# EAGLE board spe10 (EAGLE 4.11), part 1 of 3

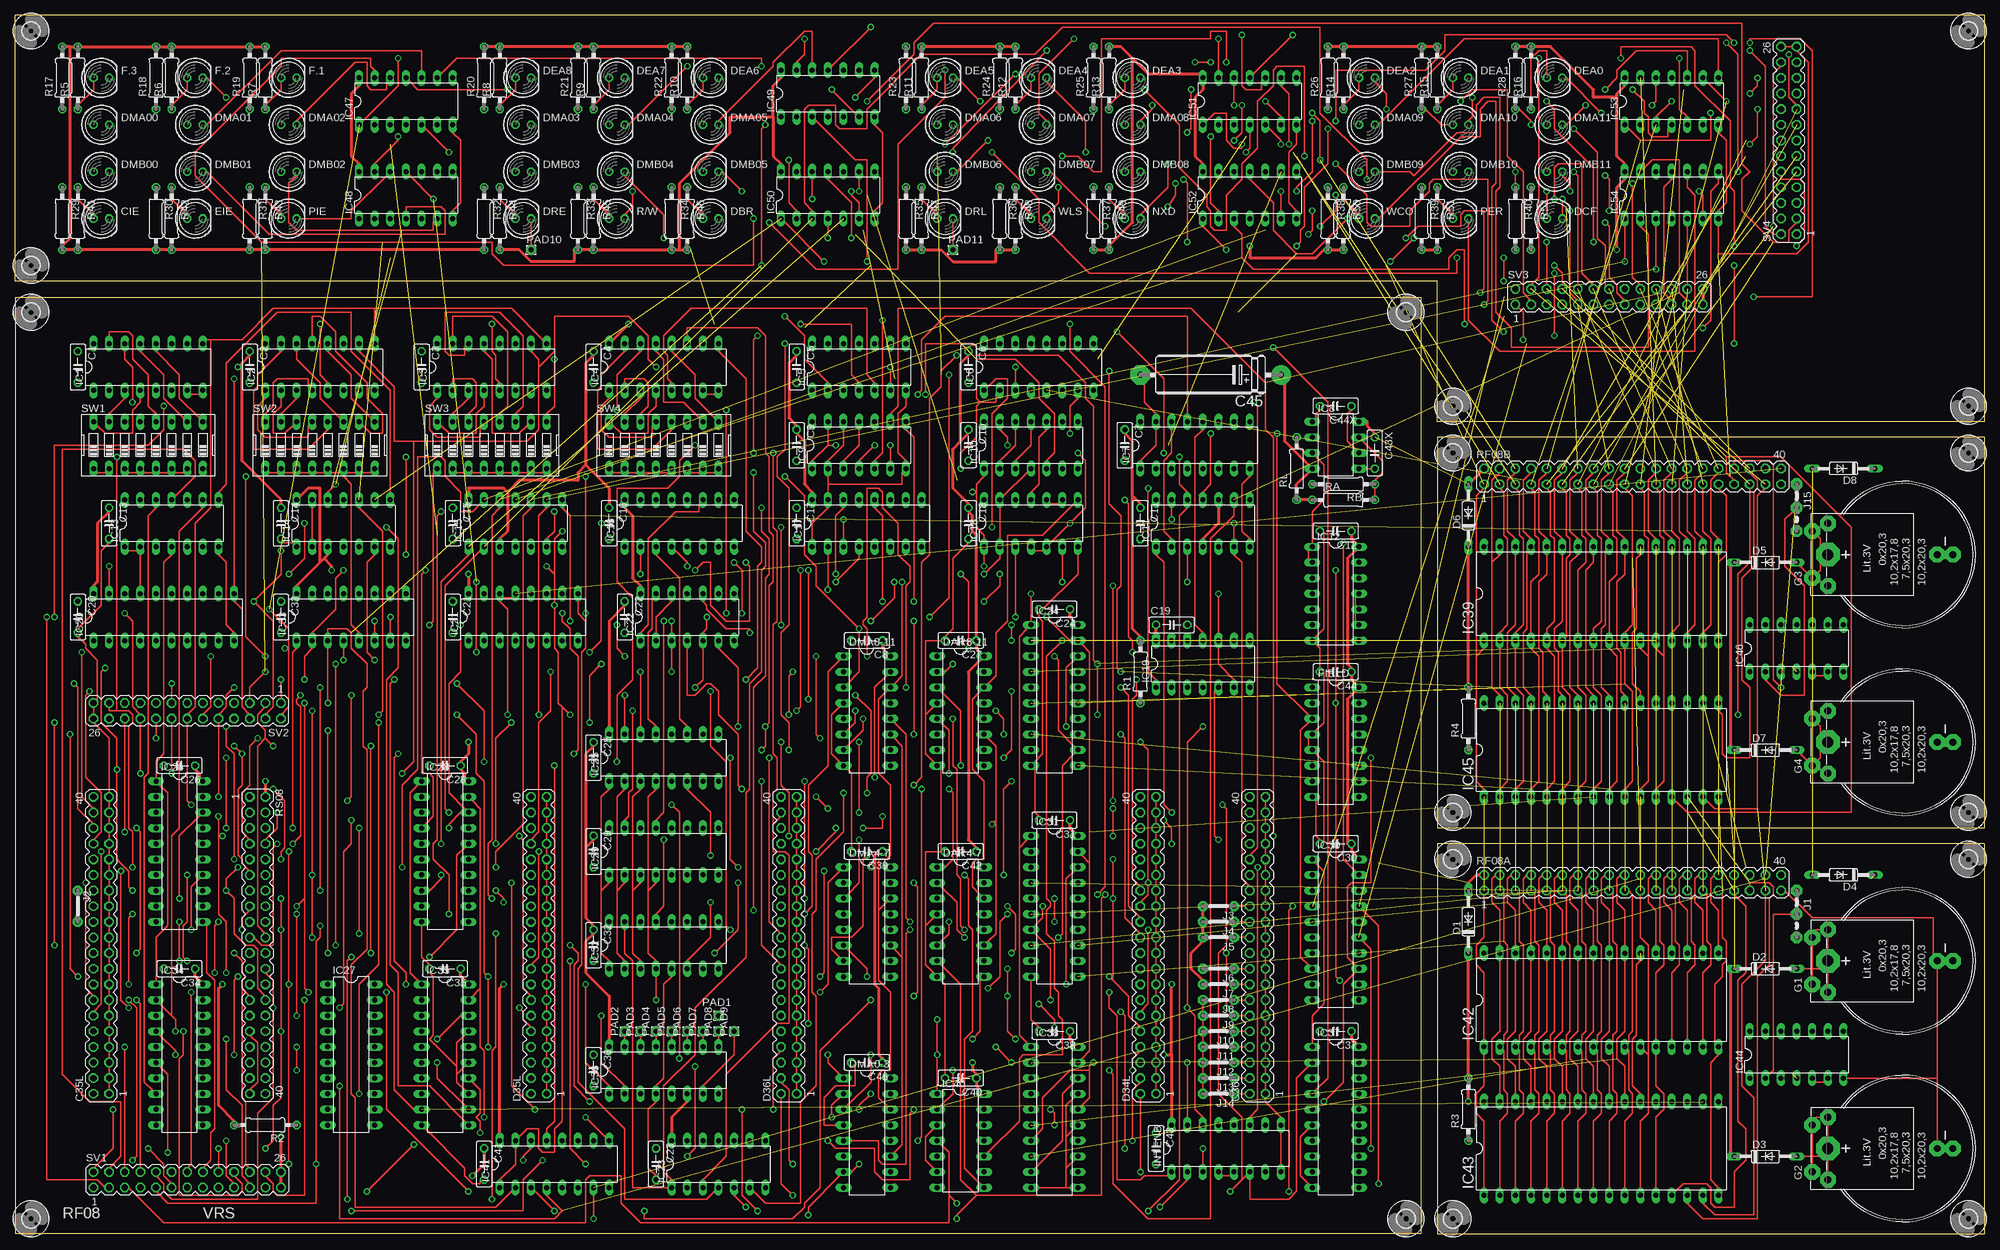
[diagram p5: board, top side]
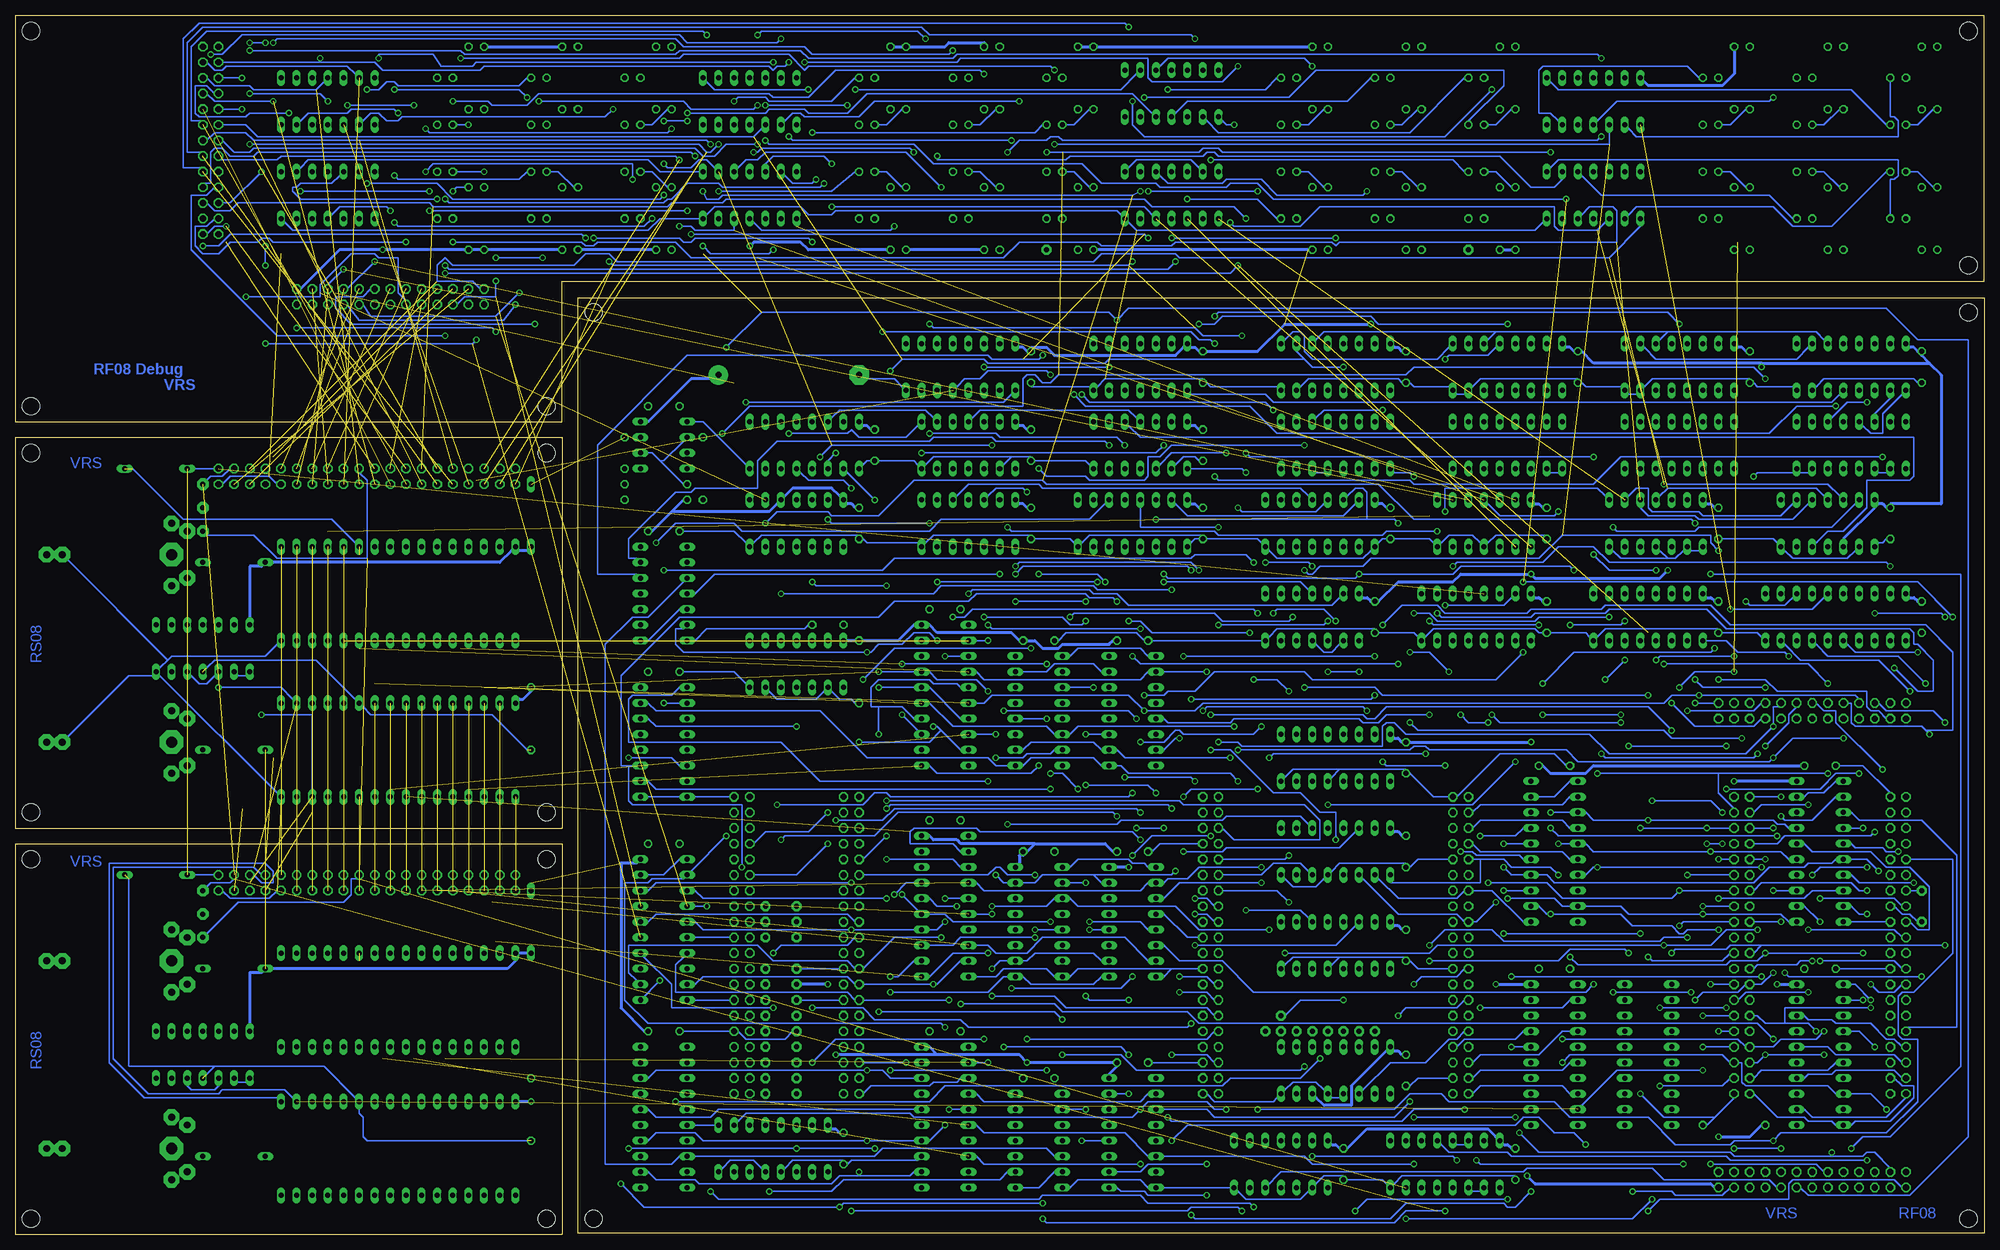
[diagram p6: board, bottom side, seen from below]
Size 320.04 x 198.12 mm. Coordinates in mm from the lower left corner, seen from the top.
Outline: 0.01,0.17 228.59,0.17 228.59,152.24 0.01,152.24 0.01,0.17
Outline: 320.04,63.5 231.14,63.5 231.14,0 320.04,0 320.04,63.5
Outline: 231.14,129.54 231.14,66.04 320.04,66.04 320.04,129.54 231.14,129.54
Outline: 320.04,132.08 231.14,132.08 231.14,154.94 0,154.94 0,198.12 320.04,198.12 320.04,132.08
Copper layers (1*16): Top 0.035mm / dielectric 1.5mm / Bottom 0.035mm
Design rules "olimex10mil": minimum track width 10mil, minimum drill 24mil, track to track 10mil, track to pad 10mil, pad to pad 10mil, via to via 10mil, smd to smd 10mil, copper to edge 40mil, drill to drill 10mil, minimum pad ring 10mil, minimum via ring 8mil, stop-mask expansion 0mil, vias tented up to drill 0mil, thermal gap 10mil
Net classes: 1 Power: width 0.508 mm

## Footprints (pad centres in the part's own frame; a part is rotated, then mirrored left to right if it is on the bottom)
C050-025X075 = drill 0.813 octagon: 1 -2.54,0; 2 2.54,0
MA20-2 = drill 1.016 octagon: 1 -24.13,-1.27; 2 -24.13,1.27; 3 -21.59,-1.27; 4 -21.59,1.27; 5 -19.05,-1.27; 6 -19.05,1.27; 7 -16.51,-1.27; 8 -16.51,1.27; 9 -13.97,-1.27; 10 -13.97,1.27; 11 -11.43,-1.27; 12 -11.43,1.27; 13 -8.89,-1.27; 14 -8.89,1.27; 15 -6.35,-1.27; 16 -6.35,1.27; 17 -3.81,-1.27; 18 -3.81,1.27; 19 -1.27,-1.27; 20 -1.27,1.27; 21 1.27,-1.27; 22 1.27,1.27; 23 3.81,-1.27; 24 3.81,1.27; 25 6.35,-1.27; 26 6.35,1.27; 27 8.89,-1.27; 28 8.89,1.27; 29 11.43,-1.27; 30 11.43,1.27; 31 13.97,-1.27; 32 13.97,1.27; 33 16.51,-1.27; 34 16.51,1.27; 35 19.05,-1.27; 36 19.05,1.27; 37 21.59,-1.27; 38 21.59,1.27; 39 24.13,-1.27; 40 24.13,1.27
E22-6 = drill 1.016 pad 3.15 round: + -11.43,0 | drill 1.016 pad 3.15 octagon: - 11.43,0
LED5MM = drill 0.813 octagon: A -1.27,0; K 1.27,0
DO35-10 = drill 0.813 long: A 5.08,0; C -5.08,0
DIL16 = drill 0.813 long: 1 -8.89,-3.81; 2 -6.35,-3.81; 3 -3.81,-3.81; 4 -1.27,-3.81; 5 1.27,-3.81; 6 3.81,-3.81; 7 6.35,-3.81; 8 8.89,-3.81; 9 8.89,3.81; 10 6.35,3.81; 11 3.81,3.81; 12 1.27,3.81; 13 -1.27,3.81; 14 -3.81,3.81; 15 -6.35,3.81; 16 -8.89,3.81
B2430UNI = drill 1.118 pad 2.54 octagon: + 3.81,14.605; +@1 -3.81,14.605; +@2 -5.08,12.065; +@3 5.08,12.065; - 0,-5.715; -@1 0,-8.255 | drill 1.803 pad 3.81 octagon: +@4 0,12.065
DIL14 = drill 0.813 long: 1 -7.62,-3.81; 2 -5.08,-3.81; 3 -2.54,-3.81; 4 0,-3.81; 5 2.54,-3.81; 6 5.08,-3.81; 7 7.62,-3.81; 8 7.62,3.81; 9 5.08,3.81; 10 2.54,3.81; 11 0,3.81; 12 -2.54,3.81; 13 -5.08,3.81; 14 -7.62,3.81
DIL08 = drill 0.813 long: 1 -3.81,-3.81; 2 -1.27,-3.81; 3 1.27,-3.81; 4 3.81,-3.81; 5 3.81,3.81; 6 1.27,3.81; 7 -1.27,3.81; 8 -3.81,3.81
DIL20 = drill 0.813 long: 1 -11.43,-3.81; 2 -8.89,-3.81; 3 -6.35,-3.81; 4 -3.81,-3.81; 5 -1.27,-3.81; 6 1.27,-3.81; 7 3.81,-3.81; 8 6.35,-3.81; 9 8.89,-3.81; 10 11.43,-3.81; 11 11.43,3.81; 12 8.89,3.81; 13 6.35,3.81; 14 3.81,3.81; 15 1.27,3.81; 16 -1.27,3.81; 17 -3.81,3.81; 18 -6.35,3.81; 19 -8.89,3.81; 20 -11.43,3.81
DIL32 = drill 0.813 long: 1 -19.05,-7.62; 2 -16.51,-7.62; 3 -13.97,-7.62; 4 -11.43,-7.62; 5 -8.89,-7.62; 6 -6.35,-7.62; 7 -3.81,-7.62; 8 -1.27,-7.62; 9 1.27,-7.62; 10 3.81,-7.62; 11 6.35,-7.62; 12 8.89,-7.62; 13 11.43,-7.62; 14 13.97,-7.62; 15 16.51,-7.62; 16 19.05,-7.62; 17 19.05,7.62; 18 16.51,7.62; 19 13.97,7.62; 20 11.43,7.62; 21 8.89,7.62; 22 6.35,7.62; 23 3.81,7.62; 24 1.27,7.62; 25 -1.27,7.62; 26 -3.81,7.62; 27 -6.35,7.62; 28 -8.89,7.62; 29 -11.43,7.62; 30 -13.97,7.62; 31 -16.51,7.62; 32 -19.05,7.62
04C = drill 0.813 pad 1.905 octagon: 1 -1.905,0; 2 1.905,0; 3 5.715,0
05 = drill 0.813 pad 1.6 octagon: 1 -2.54,0; 2 2.54,0
1,6/0,8 = drill 0.813 pad 1.6 octagon: 1 0,0
0207/10 = drill 0.813 octagon: 1 -5.08,0; 2 5.08,0
MA13-2 = drill 1.016 octagon: 1 -15.24,-1.27; 2 -15.24,1.27; 3 -12.7,-1.27; 4 -12.7,1.27; 5 -10.16,-1.27; 6 -10.16,1.27; 7 -7.62,-1.27; 8 -7.62,1.27; 9 -5.08,-1.27; 10 -5.08,1.27; 11 -2.54,-1.27; 12 -2.54,1.27; 13 0,-1.27; 14 0,1.27; 15 2.54,-1.27; 16 2.54,1.27; 17 5.08,-1.27; 18 5.08,1.27; 19 7.62,-1.27; 20 7.62,1.27; 21 10.16,-1.27; 22 10.16,1.27; 23 12.7,-1.27; 24 12.7,1.27; 25 15.24,-1.27; 26 15.24,1.27
EDG-08 = drill 0.813 long: 1 -8.89,-3.81; 2 -6.35,-3.81; 3 -3.81,-3.81; 4 -1.27,-3.81; 5 1.27,-3.81; 6 3.81,-3.81; 7 6.35,-3.81; 8 8.89,-3.81; 9 8.89,3.81; 10 6.35,3.81; 11 3.81,3.81; 12 1.27,3.81; 13 -1.27,3.81; 14 -3.81,3.81; 15 -6.35,3.81; 16 -8.89,3.81
2,8 = hole 2.8: 0,0

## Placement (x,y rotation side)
C1  0.1  [C050-025X075]  10.16,140.97 270 top
C2  0.1  [C050-025X075]  38.1,140.97 270 top
C3  0.1  [C050-025X075]  66.04,140.97 270 top
C4  0.1  [C050-025X075]  93.98,140.97 270 top
C5  0.1  [C050-025X075]  127,140.97 270 top
C6  0.1  [C050-025X075]  154.94,140.97 270 top
C7  0.1  [C050-025X075]  180.34,128.27 270 top
C8  0.1  [C050-025X075]  138.43,96.52 180 top
C9  0.1  [C050-025X075]  127,128.27 270 top
C10  0.1  [C050-025X075]  154.94,128.27 270 top
C11  0.1  [C050-025X075]  182.88,115.57 270 top
C12  0.1  [C050-025X075]  214.63,114.3 180 top
C13  0.1  [C050-025X075]  15.24,115.57 270 top
C14  0.1  [C050-025X075]  43.18,115.57 270 top
C15  0.1  [C050-025X075]  71.12,115.57 270 top
C16  0.1  [C050-025X075]  96.52,115.57 270 top
C17  0.1  [C050-025X075]  127,115.57 270 top
C18  0.1  [C050-025X075]  154.94,115.57 270 top
C19  0.1  [C050-025X075]  187.96,99.06 0 top
C20  0.1  [C050-025X075]  10.16,100.33 270 top
C21  0.1  [C050-025X075]  71.12,100.33 270 top
C22  0.1  [C050-025X075]  99.06,100.33 270 top
C23  0.1  [C050-025X075]  104.14,11.43 270 top
C24  0.1  [C050-025X075]  168.91,101.6 180 top
C25  0.1  [C050-025X075]  93.98,77.47 270 top
C26  0.1  [C050-025X075]  26.67,76.2 180 top
C27  0.1  [C050-025X075]  153.67,96.52 180 top
C28  0.1  [C050-025X075]  69.85,76.2 180 top
C29  0.1  [C050-025X075]  93.98,62.23 270 top
C30  0.1  [C050-025X075]  214.63,63.5 180 top
C31  0.1  [C050-025X075]  168.91,67.31 180 top
C32  0.1  [C050-025X075]  93.98,46.99 270 top
C33  0.1  [C050-025X075]  43.18,100.33 270 top
C34  0.1  [C050-025X075]  26.67,43.18 180 top
C35  0.1  [C050-025X075]  69.85,43.18 180 top
C35L  [MA20-2]  13.97,46.99 90 top
C36  0.1  [C050-025X075]  93.98,26.67 270 top
C36L  [MA20-2]  201.93,46.99 90 top
C37  0.1  [C050-025X075]  214.63,33.02 180 top
C38  0.1  [C050-025X075]  168.91,33.02 180 top
C39  0.1  [C050-025X075]  138.43,62.23 180 top
C40  0.1  [C050-025X075]  153.67,25.4 180 top
C41  0.1  [C050-025X075]  76.2,11.43 270 top
C42  0.1  [C050-025X075]  153.67,62.23 180 top
C43  0.1  [C050-025X075]  185.42,13.97 270 top
C43X  .1uf  [C050-025X075]  220.98,127 270 top
C44  0.1  [C050-025X075]  214.63,91.44 180 top
C44X  .1uf  [C050-025X075]  214.63,134.62 180 top
C45  100uf  [E22-6]  194.31,139.7 180 top
C46  0.1  [C050-025X075]  138.43,27.94 180 top
CIE  [LED5MM]  13.97,165.1 0 top
D1  1N4148  [DO35-10]  236.22,50.8 90 top
D2  1N4148  [DO35-10]  284.48,43.18 0 top
D3  1N4148  [DO35-10]  284.48,12.7 0 top
D4  1N4148  [DO35-10]  297.18,58.42 180 top
D5  1N4148  [DO35-10]  284.48,109.22 0 top
D6  1N4148  [DO35-10]  236.22,116.84 90 top
D7  1N4148  [DO35-10]  284.48,78.74 0 top
D8  1N4148  [DO35-10]  297.18,124.46 180 top
D34L  [MA20-2]  184.15,46.99 90 top
D35L  [MA20-2]  85.09,46.99 90 top
D36L  [MA20-2]  125.73,46.99 90 top
DAR4-7  74LS193N  [DIL16]  153.67,50.8 270 top
DAR8-11  74LS193N  [DIL16]  153.67,85.09 270 top
DBR  [LED5MM]  113.03,165.1 0 top
DCF  [LED5MM]  250.19,165.1 0 top
DEA0  [LED5MM]  250.19,187.96 0 top
DEA1  [LED5MM]  234.95,187.96 0 top
DEA2  [LED5MM]  219.71,187.96 0 top
DEA3  [LED5MM]  181.61,187.96 0 top
DEA4  [LED5MM]  166.37,187.96 0 top
DEA5  [LED5MM]  151.13,187.96 0 top
DEA6  [LED5MM]  113.03,187.96 0 top
DEA7  [LED5MM]  97.79,187.96 0 top
DEA8  [LED5MM]  82.55,187.96 0 top
DMA00  [LED5MM]  13.97,180.34 0 top
DMA0-3  74LS193N  [DIL16]  138.43,16.51 270 top
DMA01  [LED5MM]  29.21,180.34 0 top
DMA02  [LED5MM]  44.45,180.34 0 top
DMA03  [LED5MM]  82.55,180.34 0 top
DMA04  [LED5MM]  97.79,180.34 0 top
DMA4-7  74LS193N  [DIL16]  138.43,50.8 270 top
DMA05  [LED5MM]  113.03,180.34 0 top
DMA06  [LED5MM]  151.13,180.34 0 top
DMA07  [LED5MM]  166.37,180.34 0 top
DMA08  [LED5MM]  181.61,180.34 0 top
DMA8-11  74LS193N  [DIL16]  138.43,85.09 270 top
DMA09  [LED5MM]  219.71,180.34 0 top
DMA10  [LED5MM]  234.95,180.34 0 top
DMA11  [LED5MM]  250.19,180.34 0 top
DMB00  [LED5MM]  13.97,172.72 0 top
DMB01  [LED5MM]  29.21,172.72 0 top
DMB02  [LED5MM]  44.45,172.72 0 top
DMB03  [LED5MM]  82.55,172.72 0 top
DMB04  [LED5MM]  97.79,172.72 0 top
DMB05  [LED5MM]  113.03,172.72 0 top
DMB06  [LED5MM]  151.13,172.72 0 top
DMB07  [LED5MM]  166.37,172.72 0 top
DMB08  [LED5MM]  181.61,172.72 0 top
DMB09  [LED5MM]  219.71,172.72 0 top
DMB10  [LED5MM]  234.95,172.72 0 top
DMB11  [LED5MM]  250.19,172.72 0 top
DRE  [LED5MM]  82.55,165.1 0 top
DRL  [LED5MM]  151.13,165.1 0 top
EIE  [LED5MM]  29.21,165.1 0 top
F.1  [LED5MM]  44.45,187.96 0 top
F.2  [LED5MM]  29.21,187.96 0 top
F.3  [LED5MM]  13.97,187.96 0 top
FIELD  74LS193N  [DIL16]  214.63,80.01 270 top
G1  B2430UNI  [B2430UNI]  306.7,44.45 90 top
G2  B2430UNI  [B2430UNI]  306.7,13.97 90 top
G3  B2430UNI  [B2430UNI]  306.7,110.49 90 top
G4  B2430UNI  [B2430UNI]  306.7,80.01 90 top
IC1  74LS151N  [DIL16]  21.59,140.97 0 top
IC2  74LS151N  [DIL16]  49.53,140.97 0 top
IC3  74LS151N  [DIL16]  77.47,140.97 0 top
IC4  74LS151N  [DIL16]  105.41,140.97 0 top
IC5  74LS20N  [DIL14]  137.16,140.97 0 top
IC6  74S139N  [DIL16]  166.37,140.97 0 top
IC7  74LS139N  [DIL16]  191.77,128.27 0 top
IC8  LM555N  [DIL08]  214.63,128.27 270 top
IC9  74S74N  [DIL14]  137.16,128.27 0 top
IC10  74S74N  [DIL14]  165.1,128.27 0 top
IC11  74S74N  [DIL14]  193.04,115.57 0 top
IC12  74LS00N  [DIL14]  214.63,104.14 270 top
IC13  74180N  [DIL14]  25.4,115.57 0 top
IC14  74180N  [DIL14]  53.34,115.57 0 top
IC15  74180N  [DIL14]  81.28,115.57 0 top
IC16  74S139N  [DIL16]  107.95,115.57 0 top
IC17  74S139N  [DIL16]  138.43,115.57 0 top
IC18  74LS00N  [DIL14]  165.1,115.57 0 top
IC19  7407N  [DIL14]  193.04,92.71 0 top
IC20  74S240N  [DIL20]  24.13,100.33 0 top
IC21  74LS139N  [DIL16]  82.55,100.33 0 top
IC22  7407N  [DIL14]  109.22,100.33 0 top
IC23  74S74N  [DIL14]  114.3,11.43 0 top
IC24  74S240N  [DIL20]  168.91,87.63 270 top
IC25  74S138N  [DIL16]  105.41,77.47 0 top
IC26  74S240N  [DIL20]  26.67,62.23 270 top
IC27  SPARE  [DIL20]  54.61,29.21 270 top
IC28  74LS244N  [DIL20]  69.85,62.23 270 top
IC29  74S138N  [DIL16]  105.41,62.23 0 top
IC30  74S240N  [DIL20]  214.63,49.53 270 top
IC31  74S240N  [DIL20]  168.91,53.34 270 top
IC32  74S138N  [DIL16]  105.41,46.99 0 top
IC33  74LS139N  [DIL16]  54.61,100.33 0 top
IC34  74S240N  [DIL20]  26.67,29.21 270 top
IC35  74LS244N  [DIL20]  69.85,29.21 270 top
IC36  74S138N  [DIL16]  105.41,26.67 0 top
IC37  74S240N  [DIL20]  214.63,19.05 270 top
IC38  74S240N  [DIL20]  168.91,19.05 270 top
IC39  628512  [DIL32]  257.81,104.14 0 top
IC40  74S03N  [DIL14]  153.67,15.24 270 top
IC41  74LS139N  [DIL16]  87.63,11.43 0 top
IC42  628512  [DIL32]  257.81,38.1 0 top
IC43  628512  [DIL32]  257.81,13.97 0 top
IC44  4011N  [DIL14]  289.56,29.21 0 top
IC45  628512  [DIL32]  257.81,78.74 0 top
IC46  4011N  [DIL14]  289.56,95.25 0 top
IC47  7404N  [DIL14]  63.5,184.15 0 top
IC48  7404N  [DIL14]  63.5,168.91 0 top
IC49  7404N  [DIL14]  132.08,185.42 0 top
IC50  7404N  [DIL14]  132.08,168.91 0 top
IC51  7404N  [DIL14]  200.66,184.15 0 top
IC52  7404N  [DIL14]  200.66,168.91 0 top
IC53  7404N  [DIL14]  269.24,184.15 0 top
IC54  7404N  [DIL14]  269.24,168.91 0 top
INTENB  74LS193N  [DIL16]  196.85,13.97 0 top
J1  [04C]  289.56,53.98 270 top
J2  J5MM  [05]  10.16,53.34 270 top
J3  J5MM  [05]  195.58,53.34 180 top
J4  J5MM  [05]  195.58,50.8 180 top
J5  J5MM  [05]  195.58,48.26 180 top
J6  J5MM  [05]  195.58,43.18 180 top
J7  J5MM  [05]  195.58,40.64 180 top
J8  J5MM  [05]  195.58,38.1 180 top
J9  J5MM  [05]  195.58,35.56 180 top
J10  J5MM  [05]  195.58,33.02 180 top
J11  J5MM  [05]  195.58,30.48 180 top
J12  J5MM  [05]  195.58,27.94 180 top
J13  J5MM  [05]  195.58,25.4 180 top
J14  J5MM  [05]  195.58,22.86 180 top
J15  [04C]  289.56,120.02 270 top
NXD  [LED5MM]  181.61,165.1 0 top
PAD1  [1,6/0,8]  114.3,35.56 90 top
PAD2  [1,6/0,8]  99.06,33.02 90 top
PAD3  [1,6/0,8]  101.6,33.02 90 top
PAD4  [1,6/0,8]  104.14,33.02 90 top
PAD5  [1,6/0,8]  106.68,33.02 90 top
PAD6  [1,6/0,8]  109.22,33.02 90 top
PAD7  [1,6/0,8]  111.76,33.02 90 top
PAD8  [1,6/0,8]  114.3,33.02 90 top
PAD9  [1,6/0,8]  116.84,33.02 90 top
PAD10  [1,6/0,8]  83.82,160.02 0 top
PAD11  [1,6/0,8]  152.4,160.02 0 top
PER  [LED5MM]  234.95,165.1 0 top
PIE  [LED5MM]  44.45,165.1 0 top
R1  5.1K  [0207/10]  182.88,91.44 90 top
R2  5.1K  [0207/10]  40.64,17.78 180 top
R3  10 Megohm  [0207/10]  236.22,20.32 90 top
R4  10 Megohm  [0207/10]  236.22,83.82 90 top
R5  330  [0207/10]  10.16,187.96 90 top
R6  330  [0207/10]  25.4,187.96 90 top
R7  330  [0207/10]  40.64,187.96 90 top
R8  330  [0207/10]  78.74,187.96 90 top
R9  330  [0207/10]  93.98,187.96 90 top
R10  330  [0207/10]  109.22,187.96 90 top
R11  330  [0207/10]  147.32,187.96 90 top
R12  330  [0207/10]  162.56,187.96 90 top
R13  330  [0207/10]  177.8,187.96 90 top
R14  330  [0207/10]  215.9,187.96 90 top
R15  330  [0207/10]  231.14,187.96 90 top
R16  330  [0207/10]  246.38,187.96 90 top
R17  330  [0207/10]  7.62,187.96 90 top
R18  330  [0207/10]  22.86,187.96 90 top
R19  330  [0207/10]  38.1,187.96 90 top
R20  330  [0207/10]  76.2,187.96 90 top
R21  330  [0207/10]  91.44,187.96 90 top
R22  330  [0207/10]  106.68,187.96 90 top
R23  330  [0207/10]  144.78,187.96 90 top
R24  330  [0207/10]  160.02,187.96 90 top
R25  330  [0207/10]  175.26,187.96 90 top
R26  330  [0207/10]  213.36,187.96 90 top
R27  330  [0207/10]  228.6,187.96 90 top
R28  330  [0207/10]  243.84,187.96 90 top
R29  330  [0207/10]  7.62,165.1 270 top
R30  330  [0207/10]  22.86,165.1 270 top
R31  330  [0207/10]  38.1,165.1 270 top
R32  330  [0207/10]  76.2,165.1 270 top
R33  330  [0207/10]  91.44,165.1 270 top
R34  330  [0207/10]  106.68,165.1 270 top
R35  330  [0207/10]  144.78,165.1 270 top
R36  330  [0207/10]  160.02,165.1 270 top
R37  330  [0207/10]  175.26,165.1 270 top
R38  330  [0207/10]  213.36,165.1 270 top
R39  330  [0207/10]  228.6,165.1 270 top
R40  330  [0207/10]  243.84,165.1 270 top
R41  330  [0207/10]  10.16,165.1 270 top
R42  330  [0207/10]  25.4,165.1 270 top
R43  330  [0207/10]  40.64,165.1 270 top
R44  330  [0207/10]  78.74,165.1 270 top
R45  330  [0207/10]  93.98,165.1 270 top
R46  330  [0207/10]  109.22,165.1 270 top
R47  330  [0207/10]  147.32,165.1 270 top
R48  330  [0207/10]  162.56,165.1 270 top
R49  330  [0207/10]  177.8,165.1 270 top
R50  330  [0207/10]  215.9,165.1 270 top
R51  330  [0207/10]  231.14,165.1 270 top
R52  330  [0207/10]  246.38,165.1 270 top
R/W  [LED5MM]  97.79,165.1 0 top
RA  470K  [0207/10]  215.9,119.38 0 top
RB  1.5K  [0207/10]  215.9,121.92 180 top
RF08A  [MA20-2]  262.89,57.15 0 top
RF08B  [MA20-2]  262.89,123.19 0 top
RL  1K  [0207/10]  208.28,124.46 90 top
RS08  [MA20-2]  39.37,46.99 270 top
SV1  [MA13-2]  27.94,8.89 0 top
SV2  [MA13-2]  27.94,85.09 180 top
SV3  [MA13-2]  259.08,152.4 0 top
SV4  [MA13-2]  288.29,177.8 90 top
SW1  [EDG-08]  21.59,128.27 0 top
SW2  [EDG-08]  49.53,128.27 0 top
SW3  [EDG-08]  77.47,128.27 0 top
SW4  [EDG-08]  105.41,128.27 0 top
U$1  [2,8]  2.54,149.86 0 top
U$2  [2,8]  226.06,149.86 0 top
U$3  [2,8]  2.54,2.54 0 top
U$4  [2,8]  226.06,2.54 0 top
U$5  [2,8]  233.68,2.54 0 top
U$6  [2,8]  233.68,60.96 0 top
U$7  [2,8]  317.5,60.96 0 top
U$8  [2,8]  317.5,2.54 0 top
U$9  [2,8]  317.5,68.58 0 top
U$10  [2,8]  233.68,68.58 0 top
U$11  [2,8]  233.68,127 0 top
U$12  [2,8]  317.5,127 0 top
U$13  [2,8]  2.54,157.48 0 top
U$14  [2,8]  2.54,195.58 0 top
U$15  [2,8]  233.68,134.62 0 top
U$16  [2,8]  317.5,134.62 0 top
U$17  [2,8]  317.5,195.58 0 top
WCO  [LED5MM]  219.71,165.1 0 top
WLS  [LED5MM]  166.37,165.1 0 top

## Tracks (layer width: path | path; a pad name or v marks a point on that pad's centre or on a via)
3CYC\
  Bottom 0.254: C35L.28 12.06,55.88 10.79,55.88 J2.1
601\  (via drill 0.61)
  Top 0.254: IC32.15 99.06,49.53 99.06,45.72 100.33,44.45 100.33,7.62 106.05,7.62 IC23.1 106.68,8.89 105.41,10.16 105.41,24.13 110.49,29.21 110.49,36.83 118.75,45.09 118.75,71.75 119.38,72.39 119.38,89.53 121.28,91.44 121.28,107.95 121.92,108.58 121.92,112.39 120.02,114.3 v120.02,123.83 | 132.08,128.27 129.54,125.73 IC9.1 | 132.08,128.27 132.08,130.81 IC9.13 | IC18.4 165.74,111.12 167,111.12 IC18.5 168.28,112.39 v171.45,115.57 173.99,118.11 173.99,125.73 v172.72,127 | v187.96,116.2 187.96,118.11 IC11.13 | 132.08,128.27 v133.35,128.27
  Bottom 0.254: v187.96,116.2 187.32,115.57 v171.45,115.57 | v133.35,128.27 134.62,127 v172.72,127 | v120.02,123.83 120.65,124.46 128.91,124.46 IC9.1
602\  (via drill 0.61)
  Top 0.254: v100.33,85.09 100.33,72.39 99.69,71.75 99.69,67.94 99.06,67.31 IC29.15 | v127,85.09 127.64,85.72 v127.64,107.95 | v157.48,108.58 157.48,110.49 IC18.1 157.48,113.03 157.48,113.67 156.21,114.94 156.21,120.65 | 156.21,120.65 156.21,121.92 157.48,123.19 IC10.1 | 156.21,120.65 v155.57,120.65
  Bottom 0.254: v100.33,85.09 100.97,85.72 126.36,85.72 v127,85.09 | v127.64,107.95 128.91,109.22 156.84,109.22 v157.48,108.58 | v155.57,120.65 156.21,121.28 160.66,121.28 161.93,120.02 IC18.12
604\  (via drill 0.61)
  Top 0.254: v99.06,87.63 99.06,82.55 IC25.15 | v128.91,107.95 v128.91,87 | v157.48,107.31 160.02,109.86 160.02,110.49 IC18.2 160.02,113.03 160.02,118.11 IC18.13 160.66,120.02 164.47,123.83 IC10.4
  Bottom 0.254: v99.06,87.63 99.69,87 v128.91,87 | v128.91,107.95 129.54,108.58 156.21,108.58 v157.48,107.31
611\  (via drill 0.61)
  Top 0.254: v128.27,46.99 128.91,46.35 v128.91,34.29 | INTENB.14 193.04,19.05 191.77,20.32 191.77,35.56 v190.5,36.83 190.5,80.01 v193.04,82.55
  Bottom 0.254: v128.27,46.99 105.41,46.99 102.23,50.16 IC32.14 | v128.91,34.29 129.54,33.66 165.1,33.66 166.37,34.92 180.34,34.92 182.25,36.83 v190.5,36.83 | v193.04,82.55 215.9,82.55 217.17,83.82 FIELD.14
612\  (via drill 0.61)
  Top 0.254: v130.18,62.23 133.35,65.41 v133.35,66.04 | v137.79,66.04 140.97,66.04 v140.97,67.94 | v195.58,64.14 194.94,64.77 194.94,88.27 IC19.5
  Bottom 0.254: v130.18,62.23 123.83,62.23 123.19,62.87 104.78,62.87 102.23,65.41 IC29.14 | v137.79,66.04 v133.35,66.04 | v140.97,67.94 141.6,68.58 176.53,68.58 180.34,64.77 194.94,64.77 v195.58,64.14
614\  (via drill 0.61)
  Top 0.254: v101.6,91.44 101.6,82.55 IC25.14 | v106.68,91.44 106.68,95.25 IC22.3 106.68,97.79 v106.68,99.69 | v124.46,114.94 v124.46,99.06
  Bottom 0.254: v106.68,91.44 v101.6,91.44 | v124.46,114.94 137.16,114.94 137.16,118.11 IC17.13 | v124.46,99.06 107.31,99.06 v106.68,99.69
621\  (via drill 0.61)
  Top 0.254: v105.41,64.14 105.41,53.34 104.14,52.07 IC32.13 | v125.73,78.74 125.73,83.19 124.46,84.45 124.46,97.79 125.73,99.06 125.73,121.28 123.83,123.19 123.83,126.36 125.09,127.64 v125.09,144.78 | v179.07,146.69 186.69,139.06 v186.69,127
  Bottom 0.254: v105.41,64.14 105.41,68.58 107.95,68.58 111.12,71.75 115.57,71.75 122.56,78.74 v125.73,78.74 | v125.09,144.78 125.73,145.41 127.64,145.41 128.91,146.69 v179.07,146.69 | v186.69,127 187.96,125.73 IC7.3
622\  (via drill 0.61)
  Top 0.254: v105.41,99.69 105.41,68.58 104.14,67.31 IC29.13 | v115.57,133.99 v115.57,100.97 | v146.69,136.53 147.32,137.16 147.32,145.41 151.13,149.22 190.5,149.22 190.5,133.35 IC7.13
  Bottom 0.254: v105.41,99.69 107.31,101.6 114.94,101.6 v115.57,100.97 | v115.57,133.99 116.84,135.25 145.41,135.25 v146.69,136.53
624\  (via drill 0.61)
  Top 0.254: IC25.13 104.14,82.55 102.87,83.82 102.87,97.79 103.5,98.42 103.5,103.5 IC22.13 | 163.19,62.87 163.19,32.38 164.47,31.11 IC38.1 | 163.19,62.87 164.47,64.14 IC31.1 | 163.19,62.87 163.19,97.16 164.47,98.42 IC24.1 165.1,99.69 v165.1,104.14
  Bottom 0.254: v165.1,104.14 164.47,104.78 145.41,104.78 144.78,104.14 140.97,104.14 139.06,102.23 106.05,102.23 104.78,103.5 IC22.13
641\  (via drill 0.61)
  Top 0.254: v120.02,52.7 120.02,88.9 121.92,90.81 121.92,106.68 122.56,107.31 122.56,113.03 121.28,114.3 v121.28,118.11
  Bottom 0.254: v120.02,52.7 111.12,52.7 109.86,51.44 IC32.11 | v121.28,118.11 120.65,117.47 108.58,117.47 107.31,118.75 IC16.13
642\  (via drill 0.61)
  Top 0.254: v158.75,66.67 159.38,67.31 | 159.38,67.31 159.38,79.38 158.12,80.64 DAR8-11.11 | 159.38,67.31 159.38,48.9 158.12,47.62 DAR4-7.11
  Bottom 0.254: v158.75,66.67 140.97,66.67 140.34,67.31 123.83,67.31 123.19,67.94 111.12,67.94 109.86,66.67 IC29.11
644\
  Top 0.254: IC25.11 109.22,82.55 107.95,83.82 107.95,106.68 104.14,110.49 IC16.3
645\  (via drill 0.61)
  Top 0.254: 174.62,60.33 174.62,29.84 173.35,28.57 IC38.19 | 174.62,60.33 173.35,61.59 IC31.19 | 174.62,60.33 174.62,94.61 173.35,95.89 IC24.19 171.45,96.52 v167.64,100.33 | v109.22,108.58 109.22,109.22 107.31,111.12 IC16.4 | v116.84,109.22 118.11,107.95 v118.11,100.97
  Bottom 0.254: v109.22,108.58 109.86,109.22 v116.84,109.22 | v118.11,100.97 118.75,101.6 164.47,101.6 165.74,100.33 v167.64,100.33
ACB00\  (via drill 0.61)
  Top 0.254: v182.88,10.16 182.88,22.23 D34L.2
  Bottom 0.254: IC38.3 166.37,25.4 167,24.77 170.81,24.77 171.45,24.13 180.97,24.13 182.25,22.86 D34L.2 | 182.88,9.53 186.06,9.53 187.32,8.26 208.91,8.26 209.55,8.89 215.9,8.89 217.17,10.16 IC37.12 | 182.88,9.53 174.62,9.53 173.99,10.16 IC38.12 | 182.88,9.53 v182.88,10.16
ACB01\  (via drill 0.61)
  Top 0.254: v168.28,20.32 168.91,19.68 v168.91,17.78 | v181.61,15.24 181.61,23.5 182.88,24.77 D34L.4
  Bottom 0.254: IC37.14 217.17,15.24 215.9,16.51 209.55,16.51 208.28,15.24 v181.61,15.24 173.99,15.24 IC38.14 171.45,15.24 v168.91,17.78 | v168.28,20.32 166.37,20.32 IC38.5
ACB02\  (via drill 0.61)
  Top 0.254: 174.62,26.67 171.45,26.67 167,22.23 167,17.14 165.74,15.88 IC38.7 | 174.62,26.67 174.62,22.23 173.35,20.95 IC38.16 | v175.26,27.94 174.62,27.3 174.62,26.67
  Bottom 0.254: IC37.16 217.17,20.32 215.9,19.05 207.01,19.05 205.74,20.32 173.99,20.32 IC38.16 | v175.26,27.94 182.25,27.94 D34L.6
ACB03\  (via drill 0.61)
  Top 0.254: IC38.9 165.74,10.79 170.18,15.24 170.18,22.86 172.09,24.77 IC38.18 | v181.61,26.67 181.61,28.57 182.88,29.84 D34L.8
  Bottom 0.254: IC37.18 217.17,25.4 215.9,26.67 v181.61,26.67 179.07,26.67 177.8,25.4 173.99,25.4 IC38.18
ACB04\  (via drill 0.61)
  Top 0.254: 178.44,41.27 180.97,38.73 180.97,35.56 182.88,33.66 D34L.10 | 178.44,41.27 v177.8,41.91 | 178.44,41.27 v178.44,54.61 v178.44,60.96
  Bottom 0.254: v177.8,41.91 176.53,41.91 173.99,44.45 IC31.12 | v178.44,60.96 167.64,60.96 166.37,59.69 IC31.3 | v178.44,54.61 208.28,54.61 209.55,55.88 IC30.3
ACB05\  (via drill 0.61)
  Top 0.254: v168.91,50.8 v168.91,54.61 | v184.15,49.53 184.15,37.47 182.88,36.2 D34L.12
  Bottom 0.254: IC30.5 209.55,50.8 208.28,49.53 v184.15,49.53 173.99,49.53 IC31.14 171.45,49.53 170.18,49.53 v168.91,50.8 | v168.91,54.61 166.37,54.61 IC31.5
ACB06\  (via drill 0.61)
  Top 0.254: v167,53.34 167,51.44 165.74,50.16 IC31.7 165.74,48.9 168.28,46.35 v168.28,38.1
  Bottom 0.254: v167,53.34 170.18,53.34 171.45,54.61 IC31.16 | IC30.7 211.46,45.09 212.72,43.81 212.72,39.37 184.78,39.37 183.51,38.1 D34L.14 182.25,38.1 v168.28,38.1
ACB07\  (via drill 0.61)
  Top 0.254: v170.81,40.64 170.81,57.78 172.09,59.05 IC31.18
  Bottom 0.254: IC30.9 209.55,40.64 208.28,41.91 184.78,41.91 183.51,40.64 D34L.16 182.25,40.64 v170.81,40.64 170.18,40.64 166.37,44.45 IC31.9
ACB08\  (via drill 0.61)
  Top 0.254: v168.91,93.98 169.54,93.34 169.54,81.92 172.09,79.38 IC24.12 172.09,78.11 170.18,76.2 170.18,48.9 v169.54,48.26
  Bottom 0.254: v168.91,93.98 166.37,93.98 IC24.3 | IC30.12 219.07,41.27 220.34,42.55 220.34,46.99 199.39,46.99 196.85,44.45 184.78,44.45 183.51,43.18 D34L.18 182.25,43.18 177.16,48.26 v169.54,48.26
ACB09\  (via drill 0.61)
  Top 0.254: v196.85,45.72 v196.85,36.83 | v179.71,81.28 180.34,80.64 180.34,51.44 182.88,48.9 D34L.22
  Bottom 0.254: 179.71,85.72 175.9,85.72 173.99,83.82 IC24.14 | 179.71,85.72 180.97,85.72 180.97,88.9 179.71,90.17 171.45,90.17 170.81,89.53 167,89.53 166.37,88.9 IC24.5 | v196.85,36.83 213.36,36.83 213.36,40.64 217.81,45.09 IC30.14 | v196.85,45.72 195.58,46.99 184.78,46.99 183.51,48.26 D34L.22 | 179.71,85.72 v179.71,81.28
ACB10\  (via drill 0.61)
  Top 0.254: v179.71,88.9 180.97,87.63 180.97,53.34 182.88,51.44 D34L.24
  Bottom 0.254: IC24.7 166.37,83.82 171.45,88.9 IC24.16 173.99,88.9 v179.71,88.9 | IC30.16 217.17,50.8 215.9,52.07 184.78,52.07 183.51,50.8 D34L.24
ACB11\  (via drill 0.61)
  Top 0.254: v170.81,82.55 170.81,92.08 172.09,93.34 IC24.18 | D34L.26 182.88,53.98 184.15,55.24 v184.15,57.15 184.15,78.74 v182.88,80.01
  Bottom 0.254: 169.54,81.92 170.18,82.55 v170.81,82.55 | 169.54,81.92 166.37,78.74 IC24.9 | v184.15,57.15 215.9,57.15 217.17,55.88 IC30.18 | 169.54,81.92 171.45,80.01 v182.88,80.01
ACCLEAR\  (via drill 0.61)
  Top 0.254: IC22.12 106.68,102.87 104.14,100.33 104.14,97.79 IC22.2 | v178.44,69.22 v178.44,64.77 | v130.18,71.12 v132.08,69.22 | v118.11,72.39 117.47,73.03 117.47,81.28 114.3,84.45 114.3,88.27 113.03,89.53 112.39,89.53 110.49,87.63 109.22,87.63 109.22,95.25 IC22.4
  Bottom 0.254: IC22.2 104.78,95.89 106.05,94.61 107.31,94.61 108.58,95.89 IC22.4 | v178.44,64.77 182.25,60.96 D34L.32 | v178.44,69.22 177.8,69.85 132.72,69.85 v132.08,69.22 | v130.18,71.12 128.91,72.39 v118.11,72.39
BAC00  (via drill 0.61)
  Top 0.254: v126.36,6.35 124.46,8.26 124.46,22.23 D36L.2
  Bottom 0.254: v126.36,6.35 135.89,6.35 136.53,6.99 140.34,6.99 140.97,7.62 DMA0-3.9
BAC01  (via drill 0.61)
  Top 0.254: v126.36,11.43 125.73,12.06 125.73,23.5 124.46,24.77 D36L.4
  Bottom 0.254: v126.36,11.43 135.89,11.43 137.16,10.16 140.97,10.16 DMA0-3.10
BAC02  (via drill 0.61)
  Top 0.254: v132.08,29.21 132.08,27.94 133.99,26.04 DMA0-3.1
  Bottom 0.254: v132.08,29.21 126.36,29.21 125.09,27.94 D36L.6
BAC03  (via drill 0.61)
  Top 0.254: v123.19,20.32 123.19,28.57 124.46,29.84 D36L.8 | v139.06,22.86 137.16,20.95 v137.16,20.32
  Bottom 0.254: v123.19,20.32 125.09,20.32 126.36,21.59 135.89,21.59 v137.16,20.32 138.43,19.05 173.99,19.05 174.62,19.68 201.29,19.68 202.56,18.41 INTENB.10 | v139.06,22.86 140.97,22.86 DMA0-3.15
BAC04  (via drill 0.61)
  Top 0.254: v177.8,39.37 177.8,36.83 179.07,35.56 179.07,8.89 182.88,8.89 183.51,9.53 187.32,9.53 INTENB.1 | v155.57,31.75 156.84,33.02 156.84,41.27 DAR4-7.9
  Bottom 0.254: DMA4-7.9 143.51,41.91 144.78,40.64 154.94,40.64 156.21,41.91 DAR4-7.9 158.75,41.91 159.38,41.91 161.93,39.37 v177.8,39.37 | v155.57,31.75 126.36,31.75 125.09,33.02 D36L.10
BAC05  (via drill 0.61)
  Top 0.254: v190.5,27.94 190.5,19.05 INTENB.15 | v162.56,31.75 161.29,33.02 v161.29,38.73 v161.29,43.18
  Bottom 0.254: DMA4-7.10 143.51,44.45 144.78,45.72 154.31,45.72 155.57,44.45 156.21,44.45 DAR4-7.10 158.75,44.45 160.02,44.45 v161.29,43.18 | v190.5,27.94 186.69,31.75 v162.56,31.75 | v161.29,38.73 151.13,38.73 149.22,36.83 126.36,36.83 125.09,35.56 D36L.12
BAC06  (via drill 0.61)
  Top 0.254: v151.76,72.39 152.4,71.75 152.4,60.96 151.13,59.69 DAR4-7.1 | v130.81,39.37 132.08,40.64 132.08,57.15 133.99,59.05 DMA4-7.1
  Bottom 0.254: DMA4-7.1 135.89,59.69 136.53,60.33 138.43,60.33 139.06,60.96 147.32,60.96 148.59,59.69 DAR4-7.1 | v151.76,72.39 215.9,72.39 217.17,73.66 FIELD.10 | v130.81,39.37 126.36,39.37 125.09,38.1 D36L.14
BAC07  (via drill 0.61)
  Top 0.254: v161.93,73.66 160.66,72.39 v160.66,58.42 | v130.81,41.91 131.44,42.55 v131.44,59.05
  Bottom 0.254: 144.78,58.42 143.51,57.15 DMA4-7.15 | 144.78,58.42 153.03,58.42 154.31,57.15 156.21,57.15 DAR4-7.15 158.75,57.15 159.38,57.15 v160.66,58.42 | v161.93,73.66 189.23,73.66 195.58,80.01 220.34,80.01 220.34,87 219.71,87.63 213.36,87.63 212.09,88.9 FIELD.1 | v130.81,41.91 126.36,41.91 125.09,40.64 D36L.16 | v131.44,59.05 132.08,58.42 144.78,58.42
BAC08  (via drill 0.61)
  Top 0.254: v121.28,73.66 121.28,46.99 124.46,43.81 D36L.18
  Bottom 0.254: FIELD.15 217.17,86.36 215.9,85.09 189.23,85.09 181.61,77.47 161.93,77.47 160.66,76.2 158.75,76.2 DAR8-11.9 156.21,76.2 154.94,77.47 144.78,77.47 143.51,76.2 DMA8-11.9 140.97,76.2 140.34,76.2 139.06,74.93 122.56,74.93 v121.28,73.66
BAC09  (via drill 0.61)
  Top 0.254: v122.56,77.47 122.56,50.8 124.46,48.9 D36L.22
  Bottom 0.254: DAR8-11.10 156.21,78.74 154.94,80.01 144.78,80.01 143.51,78.74 DMA8-11.10 140.97,78.74 139.7,77.47 v122.56,77.47
BAC10  (via drill 0.61)
  Top 0.254: v128.27,52.07 129.54,53.34 129.54,61.59 128.91,62.23 128.91,73.03 132.08,76.2 132.08,91.44 133.99,93.34 DMA8-11.1
  Bottom 0.254: DMA8-11.1 135.89,93.98 137.16,95.25 147.32,95.25 148.59,93.98 DAR8-11.1 | v128.27,52.07 126.36,52.07 125.09,50.8 D36L.24
BAC11  (via drill 0.61)
  Top 0.254: v128.27,54.61 v128.27,73.66 | v139.7,74.3 139.7,88.9 141.6,90.81 DMA8-11.15
  Bottom 0.254: DMA8-11.15 143.51,91.44 144.78,92.71 151.13,92.71 152.4,91.44 156.21,91.44 DAR8-11.15 | v128.27,54.61 126.36,54.61 125.09,53.34 D36L.26 | v128.27,73.66 128.91,74.3 v139.7,74.3
BADDAC\  (via drill 0.61)
  Top 0.254: v187.96,68.58 186.69,69.85 186.69,109.22 185.42,110.49 IC11.1
  Bottom 0.254: v187.96,68.58 191.13,65.41 198.12,65.41 200.03,63.5 C36L.34
BBREAK\  (via drill 0.61)
  Top 0.254: v201.29,135.25 201.93,134.62 201.93,62.87 200.66,61.59 C36L.32 | IC41.1 78.74,8.89 81.28,11.43 81.28,13.97 IC41.15 81.92,15.88 83.19,17.14 85.09,17.14 85.09,13.97 85.72,13.34 87.63,13.34 87.63,17.14 88.9,18.41 88.9,85.72 | 88.9,85.72 88.27,86.36 88.27,94.61 87.63,95.25 v87.63,102.23 87.63,107.31 | 88.9,85.72 v90.17,84.45 | v15.24,108.58 15.24,105.41 IC20.19 | 87.63,107.31 v86.36,108.58 | v158.75,114.94 158.75,133.35 161.29,135.89 161.29,139.06 159.38,139.06 158.12,137.79 IC6.1 | v88.9,114.3 87.63,113.03 87.63,107.31
  Bottom 0.254: v201.29,135.25 159.38,135.25 158.12,136.53 IC6.1 | v90.17,84.45 97.16,84.45 98.42,83.19 100.97,83.19 101.6,83.82 121.92,83.82 122.56,83.19 132.72,83.19 133.35,83.82 DMA8-11.5 | v87.63,102.23 78.11,102.23 76.83,103.5 IC21.15 | v15.24,108.58 15.88,109.22 60.96,109.22 63.5,111.76 69.22,111.76 71.75,109.22 85.72,109.22 v86.36,108.58 | v158.75,114.94 158.12,114.3 125.09,114.3 124.46,113.67 97.79,113.67 97.16,114.3 v88.9,114.3
BINIT  (via drill 0.61)
  Top 0.254: IC9.3 134.62,125.73 137.16,128.27 137.16,130.81 IC9.11 | IC10.3 162.56,125.73 165.1,128.27 165.1,130.81 IC10.11 | 123.19,66.67 123.19,62.23 125.09,62.23 125.73,61.59 125.73,34.29 123.83,34.29 115.57,26.04 115.57,12.7 111.76,8.89 IC23.3 | 123.19,66.67 124.46,67.94 D36L.38 | v123.19,127 123.19,114.94 123.83,114.3 123.83,99.69 123.19,99.06 123.19,78.11 123.83,77.47 123.83,72.39 123.19,71.75 123.19,66.67
  Bottom 0.254: IC9.11 137.79,132.72 139.06,133.99 163.19,133.99 164.47,132.72 IC10.11 | v123.19,127 132.08,127 133.99,125.09 IC9.3
BIOP1  (via drill 0.61)
  Top 0.254: v113.03,53.98 113.03,48.26 109.22,44.45 IC32.6
  Bottom 0.254: v113.03,53.98 114.94,55.88 123.83,55.88 D36L.28
BIOP2
  Bottom 0.254: IC29.6 109.86,59.05 111.12,60.33 115.57,60.33 117.47,58.42 123.83,58.42 D36L.30
BIOP4  (via drill 0.61)
  Top 0.254: v113.03,61.59 113.03,68.58 109.22,72.39 IC25.6
  Bottom 0.254: v113.03,61.59 113.67,60.96 123.83,60.96 D36L.32
BMB00
  Bottom 0.254: IC35.8 67.31,22.86 68.58,24.13 81.92,24.13 83.19,22.86 D35L.2
BMB01
  Bottom 0.254: IC35.6 67.31,27.94 68.58,26.67 81.92,26.67 83.19,25.4 D35L.4
BMB02
  Bottom 0.254: IC35.4 67.31,33.02 68.58,33.02 72.39,29.21 81.92,29.21 83.19,27.94 D35L.6
BMB03  (via drill 0.61)
  Top 0.254: v81.92,36.83 82.55,36.2 82.55,34.92 83.82,33.66 D35L.10
  Bottom 0.254: v81.92,36.83 68.58,36.83 67.31,38.1 IC35.2 | IC36.3 100.97,23.5 96.52,27.94 90.81,27.94 87,31.75 85.72,31.75 84.45,33.02 D35L.10
BMB04  (via drill 0.61)
  Top 0.254: v95.25,35.56 95.25,27.94 99.06,24.13 IC36.2 | v81.92,64.77 82.55,64.14 82.55,40.01 83.82,38.73 D35L.14
  Bottom 0.254: v95.25,35.56 93.98,36.83 85.72,36.83 84.45,38.1 D35L.14 | v81.92,64.77 76.2,64.77 74.93,66.04 IC28.17
BMB05  (via drill 0.61)
  Top 0.254: v92.71,40.64 92.71,27.94 96.52,24.13 IC36.1 | v85.09,62.23 85.09,45.09 83.82,43.81 D35L.18
  Bottom 0.254: v92.71,40.64 91.44,41.91 85.72,41.91 84.45,43.18 D35L.18 | v85.09,62.23 83.19,62.23 82.55,61.59 75.56,61.59 74.93,60.96 IC28.15
BMB06  (via drill 0.61)
  Top 0.254: v78.11,55.88 79.38,54.61 v79.38,53.98 | 100.33,55.88 100.33,45.72 101.6,44.45 IC32.3 | 100.33,55.88 101.6,57.15 IC29.3 | 100.33,55.88 100.33,71.12 101.6,72.39 IC25.3
  Bottom 0.254: v78.11,55.88 74.93,55.88 IC28.13 | v79.38,53.98 82.55,50.8 83.19,50.8 D35L.24 84.45,50.8 85.72,52.07 95.25,52.07 100.97,57.78 IC29.3
BMB07
  Top 0.254: 97.79,55.88 97.79,45.72 99.06,44.45 IC32.2 | 97.79,55.88 99.06,57.15 IC29.2 | 97.79,55.88 97.79,71.12 99.06,72.39 IC25.2
  Bottom 0.254: IC28.11 74.93,50.8 80.01,55.88 83.19,55.88 D35L.28 84.45,55.88 85.72,54.61 95.25,54.61 98.42,57.78 IC29.2
BMB08  (via drill 0.61)
  Top 0.254: v69.22,58.42 69.22,57.78 67.31,55.88 IC28.8 | 95.25,55.88 95.25,45.72 96.52,44.45 IC32.1 | 95.25,55.88 96.52,57.15 IC29.1 | 95.25,55.88 95.25,71.12 96.52,72.39 IC25.1
  Bottom 0.254: v69.22,58.42 70.48,59.69 76.83,59.69 78.11,60.96 81.92,60.96 | 81.92,60.96 83.19,60.96 D35L.32 | 81.92,60.96 81.92,57.15 96.52,57.15 IC29.1
BMB09  (via drill 0.61)
  Top 0.254: v134.62,116.2 134.62,113.03 IC17.3 | v87,91.44 87,85.09 85.09,83.19 85.09,65.41 83.82,64.14 D35L.34 | v93.34,94.61 95.25,96.52 v95.25,115.57
  Bottom 0.254: IC28.6 67.31,60.96 68.58,62.23 81.92,62.23 83.19,63.5 D35L.34 | 100.33,116.2 100.33,120.65 100.97,121.28 102.23,121.28 103.5,120.02 IC16.14 | 100.33,116.2 v134.62,116.2 | v87,91.44 90.17,94.61 v93.34,94.61 | v95.25,115.57 95.89,116.2 100.33,116.2
BMB10  (via drill 0.61)
  Top 0.254: v101.6,107.31 101.6,110.49 IC16.2 | v133.35,107.31 133.35,116.84 134.62,118.11 IC17.14 | v66.67,107.95 66.04,107.31 66.04,74.93 67.31,74.93 67.94,74.3 67.94,67.94 66.67,66.67 IC28.4
  Bottom 0.254: IC28.4 67.31,66.04 68.58,67.31 81.92,67.31 83.19,66.04 D35L.36 | v133.35,107.31 132.72,106.68 102.23,106.68 v101.6,107.31 86.36,107.31 85.09,108.58 67.31,108.58 v66.67,107.95
BMB11
  Bottom 0.254: IC28.2 67.31,71.12 68.58,69.85 81.92,69.85 83.19,68.58 D35L.38
BRK_RQ
  Bottom 0.254: IC50.13 127.64,173.35 128.91,174.62 137.79,174.62 139.06,173.35 IC50.8
BRK_RQ\  (via drill 0.61)  (1 unrouted)
  Top 0.254: C36L.28 200.66,56.52 199.39,57.78 199.39,109.22 198.12,110.49 IC11.6 198.12,113.03 v198.12,115.57 | v21.59,13.97 24.13,11.43 24.13,9.53 25.4,8.26 SV1.11 | v44.45,107.31 46.99,109.86 v46.99,115.57 | v137.16,169.54 IC50.9 | v282.57,152.4 292.1,152.4 292.1,192.41 290.19,194.31 281.94,194.31 v281.94,193.68 | v279.4,193.68 278.13,194.94 232.41,194.94 232.41,192.41 229.24,189.23 214.63,189.23 v214.63,180.97 | v210.82,180.97 210.82,172.72 208.28,170.18 v208.28,169.54
  Bottom 0.254: v21.59,13.97 19.68,15.88 15.24,15.88 3.81,27.3 3.81,107.31 v44.45,107.31 | v46.99,115.57 47.62,116.2 92.71,116.2 98.42,121.92 152.4,121.92 153.03,122.56 173.99,122.56 179.71,116.84 187.32,116.84 187.96,117.47 196.22,117.47 v198.12,115.57 | v137.16,169.54 138.43,168.91 205.1,168.91 205.74,168.28 207.65,168.28 v208.28,169.54 | v282.57,152.4 270.51,152.4 270.51,154.31 265.43,159.38 261.62,159.38 260.99,158.75 257.81,158.75 257.81,153.03 256.54,151.76 SV3.11 | v279.4,193.68 v281.94,193.68 | v210.82,180.97 v214.63,180.97
BTS1  (via drill 0.61)
  Top 0.254: v190.5,106.05 190.5,110.49 IC11.3 | v178.44,105.41 v178.44,70.48
  Bottom 0.254: v190.5,106.05 189.87,105.41 v178.44,105.41 | v178.44,70.48 130.81,70.48 130.18,69.85 110.49,69.85 107.95,67.31 107.95,64.14 121.92,64.14 123.83,66.04 D36L.36
BUSY
  Top 0.254: IC11.2 187.96,113.03 186.69,114.3 186.69,125.73 187.96,127 187.96,130.81 IC7.14
  Bottom 0.254: IC10.9 170.81,132.72 172.09,133.99 186.06,133.99 187.32,132.72 IC7.14
BWCO
  Bottom 0.254: IC52.8 208.91,172.72 215.26,172.72 217.17,174.62 272.42,174.62 273.69,173.35 IC54.9
BWCO\  (via drill 0.61)  (1 unrouted)
  Top 0.254: v161.29,128.27 161.29,129.54 160.02,130.81 IC10.13 | v189.23,126.36 189.23,121.92 190.5,120.65 IC11.12 190.5,118.11 189.23,116.84 189.23,8.89 v184.15,3.81 | v34.29,15.24 34.29,9.53 35.56,8.26 SV1.19 | v120.65,3.81 118.11,6.35 v118.11,20.32 | v214.63,173.99 219.71,168.91 219.71,164.47 220.34,163.83 226.69,163.83 226.69,166.37 229.87,169.54 229.87,170.81 230.5,171.45 239.4,171.45 239.4,151.76 v238.76,151.13
  Bottom 0.254: v161.29,128.27 187.32,128.27 v189.23,126.36 | C35L.32 12.06,60.96 5.08,60.96 5.08,45.72 11.43,39.37 13.34,39.37 13.97,38.73 13.97,32.38 13.34,31.75 10.79,31.75 10.79,21.59 15.88,16.51 33.02,16.51 v34.29,15.24 40.64,15.24 41.27,14.61 50.16,14.61 54.61,19.05 67.31,19.05 69.85,21.59 87,21.59 88.27,22.86 93.34,22.86 95.89,20.32 v118.11,20.32 | v184.15,3.81 129.54,3.81 128.91,4.45 121.28,4.45 v120.65,3.81 | v214.63,173.99 214,173.35 210.19,173.35 208.91,174.62 207.65,174.62 206.38,173.35 IC52.9 | v238.76,151.13 240.66,148.59 264.16,148.59 266.06,151.13 SV3.19
CIE  (via drill 0.61)  (1 unrouted)
  Top 0.254: v220.34,13.97 220.34,46.35 IC30.15 | v193.04,13.97 INTENB.3 | v149.86,34.92 v149.86,29.21 IC40.1 | v179.71,36.2 180.34,35.56 v180.34,13.97 | v54.61,3.81 82.55,3.81 82.55,8.89 v85.72,12.06 | v109.22,12.7 110.49,13.97 v110.49,27.3 | v170.18,175.26 172.72,175.26 175.26,172.72 176.53,172.72 176.53,194.31 194.31,194.31 194.31,195.58 196.85,195.58 v196.85,190.5 | SV3.1 245.11,149.86 v245.11,145.41 | v279.4,157.48 v279.4,144.78 | v279.4,160.66 279.4,169.54 278.76,170.18 278.76,180.97 273.05,186.69 273.05,192.41 272.42,193.04 260.99,193.04 v260.99,191.13
  Bottom 0.254: v220.34,13.97 v193.04,13.97 v180.34,13.97 | v149.86,34.92 151.13,36.2 v179.71,36.2 | v54.61,3.81 52.7,5.71 31.75,5.71 31.75,8.26 31.11,8.89 14.61,8.89 13.34,7.62 SV1.1 | v85.72,12.06 86.36,12.7 v109.22,12.7 | v110.49,27.3 111.12,26.67 137.79,26.67 140.34,29.21 v149.86,29.21 | IC48.9 68.58,171.45 69.85,170.18 73.66,170.18 78.74,175.26 124.46,175.26 125.09,175.9 126.36,175.9 127,175.26 148.59,175.26 149.22,174.62 170.18,174.62 v170.18,175.26 | v196.85,190.5 245.11,190.5 245.75,189.87 250.82,189.87 252.09,191.77 260.99,191.77 v260.99,191.13 | v245.11,145.41 245.75,144.78 v279.4,144.78 | v279.4,160.66 v279.4,157.48
DA00\
  Top 0.254: C36L.2 200.03,22.86 198.75,22.86 J14.1
DA01\
  Top 0.254: C36L.4 200.03,25.4 198.75,25.4 J13.1
DA02\
  Top 0.254: C36L.6 200.03,27.94 198.75,27.94 J12.1
DA03\
  Top 0.254: C36L.8 200.03,30.48 198.75,30.48 J11.1
DA04\
  Top 0.254: C36L.10 200.03,33.02 198.75,33.02 J10.1
DA05\
  Top 0.254: C36L.12 200.03,35.56 198.75,35.56 J9.1
DA06\
  Top 0.254: C36L.14 200.03,38.1 198.75,38.1 J8.1
DA07\
  Top 0.254: C36L.16 200.03,40.64 198.75,40.64 J7.1
DA08\
  Top 0.254: C36L.18 200.03,43.18 198.75,43.18 J6.1
DA09\
  Top 0.254: C36L.22 200.03,48.26 198.75,48.26 J5.1
DA10\
  Top 0.254: C36L.24 200.03,50.8 198.75,50.8 J4.1
DA11\
  Top 0.254: C36L.26 200.03,53.34 198.75,53.34 J3.1
DAR04  (via drill 0.61)  (1 unrouted)
  Top 0.254: 156.21,6.35 153.67,8.89 153.67,40.64 150.5,43.81 DAR4-7.7 | 156.21,6.35 176.53,6.35 176.53,54.61 v177.16,55.24 | v50.8,86.36 50.8,95.25 IC33.3 50.8,97.79 50.8,98.42 53.98,98.42 54.61,97.79 54.61,95.25 57.15,92.71 57.15,88.9 56.52,88.27 56.52,79.38 57.15,78.74 57.15,46.35 54.61,43.81 54.61,22.86 55.24,22.23 55.24,4.45 78.11,4.45 80.64,6.99 IC41.2 | 156.21,6.35 153.03,3.17 v153.03,2.54 | v87.63,3.81 84.45,6.99 IC41.3 | v121.92,180.34 121.28,179.71 v121.28,157.48 | v250.19,156.21 v250.19,146.05
  Bottom 0.254: v177.16,55.24 175.26,57.15 173.99,57.15 IC31.17 | IC41.2 81.92,6.99 83.19,6.99 IC41.3 | v50.8,86.36 46.99,82.55 37.47,82.55 36.2,83.82 SV2.8 | v153.03,2.54 152.4,1.91 95.89,1.91 93.98,3.81 v87.63,3.81 | v121.92,180.34 123.19,180.34 123.83,180.97 IC49.1 | v121.28,157.48 122.56,156.21 v250.19,156.21 | v250.19,146.05 277.5,146.05 291.46,160.02 291.46,168.91 288.93,168.91 287.65,170.18 SV4.8
DAR05  (via drill 0.61)  (3 unrouted)
  Top 0.254: v151.76,50.8 151.76,48.9 150.5,47.62 DAR4-7.6 | v46.99,90.17 46.99,93.98 48.26,95.25 IC33.2 48.26,97.79 52.07,101.6 52.07,106.68 v53.34,107.95 | v35.56,88.9 34.29,87.63 34.29,85.72 33.02,84.45 SV2.10 33.02,83.19 v33.02,71.12 | v175.9,55.24 177.16,56.52 177.16,137.79 171.45,143.51 v171.45,147.96 | v120.65,146.05 120.02,145.41 v120.02,127 | v63.5,126.36 v63.5,110.49 | IC43.1 238.76,7.62 238.76,18.41 237.49,19.68 237.49,22.86 238.76,24.13 238.76,29.21 IC42.1 238.76,31.75 238.76,42.55 237.49,43.81 237.49,46.99 238.76,48.26 238.76,55.24 RF08A.1 | 237.49,93.98 237.49,73.66 238.76,72.39 IC45.1 | 237.49,93.98 238.76,95.25 IC39.1 | 237.49,93.98 237.49,120.02 238.76,121.28 RF08B.1 | v138.43,158.12 138.43,174.62 136.53,174.62 130.18,180.97 IC49.3 | v223.52,158.12 v227.33,161.93 | v289.56,160.66 290.83,161.93 290.83,170.81 290.19,171.45 287.02,171.45 287.02,172.09 SV4.10
  Bottom 0.254: v151.76,50.8 167.64,50.8 168.91,52.07 171.45,52.07 IC31.15 173.35,52.7 v175.9,55.24 | v46.99,90.17 45.72,88.9 v35.56,88.9 | v33.02,71.12 37.47,71.12 RS08.1 | v171.45,147.96 170.81,147.32 128.27,147.32 127,146.05 v120.65,146.05 | v120.02,127 119.38,126.36 v63.5,126.36 | v63.5,110.49 60.96,107.95 v53.34,107.95 | v138.43,158.12 139.06,157.48 222.88,157.48 v223.52,158.12 | v227.33,161.93 227.97,162.56 285.12,162.56 287.02,160.66 v289.56,160.66
DAR06  (via drill 0.61)  (3 unrouted)
  Top 0.254: v154.31,48.26 153.03,49.53 153.03,53.98 150.5,56.52 DAR4-7.2 | v45.09,66.04 45.09,94.61 45.72,95.25 IC33.1 | v31.75,93.98 31.75,85.72 30.48,84.45 SV2.12 | v146.05,57.15 146.69,56.52 146.69,39.37 v146.05,38.73 | v139.06,38.1 130.81,29.84 130.81,7.62 128.27,5.08 128.27,4.45 126.36,2.54 102.23,2.54 v102.23,3.81 | v77.47,5.71 77.47,29.84 78.11,30.48 v78.11,48.9 | v55.88,48.9 v55.88,66.04 | IC43.30 243.84,22.86 243.84,27.3 242.57,28.57 242.57,31.75 243.84,33.02 243.84,44.45 IC42.30 243.84,46.99 243.84,52.7 242.57,53.98 242.57,57.78 243.21,58.42 RF08A.6 | IC45.30 243.84,87.63 242.57,88.9 242.57,97.79 243.84,99.06 243.84,110.49 IC39.30 243.84,113.03 242.57,114.3 242.57,122.56 243.84,123.83 RF08B.6 | v210.82,182.25 212.09,180.97 v212.09,174.62
  Bottom 0.254: v154.31,48.26 166.37,48.26 167.64,46.99 171.45,46.99 IC31.13 | RS08.6 41.27,66.04 v45.09,66.04 v55.88,66.04 | v31.75,93.98 32.38,94.61 40.01,94.61 41.91,96.52 45.09,96.52 IC33.1 | v146.05,57.15 148.59,57.15 DAR4-7.2 | v146.05,38.73 145.41,38.1 v139.06,38.1 | v102.23,3.81 100.33,5.71 v77.47,5.71 | v78.11,48.9 v55.88,48.9 | v210.82,182.25 198.12,182.25 197.49,182.88 191.77,182.88 191.13,182.25 184.78,182.25 181.61,185.42 138.43,185.42 135.25,182.25 IC49.5 | v212.09,174.62 212.72,175.26 276.86,175.26 277.5,174.62 287.02,174.62 SV4.12
DAR07  (via drill 0.61)  (3 unrouted)
  Top 0.254: v161.29,53.34 162.56,52.07 162.56,46.35 v161.93,45.72 | v28.57,69.85 27.94,70.48 27.94,83.19 SV2.14 27.94,84.45 29.21,85.72 29.21,115.57 31.75,118.11 31.75,145.41 | 31.75,145.41 36.83,145.41 41.91,150.5 58.42,150.5 | 31.75,145.41 31.11,145.41 IC1.9 | 58.42,150.5 58.42,146.05 IC2.9 | 58.42,150.5 80.64,150.5 85.72,145.41 IC3.9 | v116.2,49.53 115.57,50.16 115.57,76.83 113.03,79.38 v113.03,88.27 | v118.75,90.17 120.65,92.08 120.65,108.58 121.28,109.22 121.28,111.76 118.75,114.3 118.75,139.06 114.3,143.51 IC4.9 | IC43.2 241.3,7.62 241.3,18.41 242.57,19.68 242.57,22.86 241.94,23.5 241.94,29.84 IC42.2 241.94,31.11 241.94,32.38 242.57,33.02 242.57,46.99 241.94,47.62 241.94,55.88 RF08A.3 | IC45.2 241.3,72.39 242.57,73.66 242.57,87.63 241.3,88.9 241.3,95.25 IC39.2 241.3,97.79 242.57,99.06 242.57,113.03 241.94,113.67 241.94,120.65 241.3,121.28 RF08B.3 | v199.39,177.16 199.39,176.53 198.12,176.53 196.85,177.8 196.85,182.25 194.94,182.25 193.68,180.97 IC51.1
  Bottom 0.254: v161.29,53.34 152.4,53.34 151.13,54.61 DAR4-7.3 148.59,54.61 147.32,53.34 131.44,53.34 127.64,49.53 v116.2,49.53 | v161.93,45.72 167.64,45.72 171.45,41.91 IC31.11 | v28.57,69.85 36.2,69.85 37.47,68.58 RS08.3 | IC4.9 113.67,145.41 112.39,146.69 111.12,146.69 110.49,146.05 110.49,143.51 109.22,142.24 88.9,142.24 87,144.15 IC3.9 | v113.03,88.27 114.94,90.17 v118.75,90.17 | v199.39,177.16 204.47,177.16 206.38,175.26 208.28,175.26 209.55,176.53 281.31,176.53 281.94,175.9 284.48,175.9 286.38,177.8 SV4.14
DAR08  (via drill 0.61)  (3 unrouted)
  Top 0.254: v160.66,77.47 161.93,78.74 v161.93,88.27 | v25.4,74.93 25.4,83.19 SV2.16 | 85.09,140.97 85.09,130.81 83.19,128.91 64.77,128.91 | 85.09,140.97 85.09,142.24 83.82,143.51 IC3.10 | 64.77,128.91 61.59,128.91 61.59,137.79 55.88,143.51 IC2.10 | v104.14,140.97 102.87,142.24 102.87,146.05 99.69,149.22 87.63,149.22 87.63,143.51 85.09,140.97 | v62.87,74.93 64.77,76.83 64.77,128.91 | v179.71,91.44 179.07,92.08 179.07,104.78 179.71,105.41 179.71,116.84 177.8,118.75 v177.8,140.34 | IC43.31 241.3,22.86 241.3,27.3 240.03,28.57 240.03,31.75 241.3,33.02 241.3,44.45 IC42.31 241.3,46.99 241.3,52.7 240.03,53.98 240.03,57.78 240.66,58.42 RF08A.4 | 240.03,109.22 240.03,88.9 241.3,87.63 IC45.31 | 240.03,109.22 241.3,110.49 IC39.31 | 240.03,109.22 240.03,122.56 241.3,123.83 RF08B.4
  Bottom 0.254: v160.66,77.47 156.21,77.47 155.57,78.11 151.76,78.11 151.13,78.74 DAR8-11.7 | v161.93,88.27 163.83,90.17 170.18,90.17 171.45,91.44 IC24.17 173.99,91.44 v179.71,91.44 | 43.18,74.93 43.18,71.75 40.64,69.22 RS08.4 | 43.18,74.93 v25.4,74.93 | IC1.10 28.57,144.15 30.48,142.24 53.34,142.24 55.24,144.15 IC2.10 | 110.49,142.24 109.22,140.97 v104.14,140.97 | 110.49,142.24 111.76,143.51 IC4.10 | v62.87,74.93 43.18,74.93 | v177.8,140.34 175.9,142.24 162.56,142.24 161.93,141.6 142.88,141.6 142.24,142.24 110.49,142.24 | IC51.3 198.75,179.71 200.03,178.44 280.67,178.44 282.57,180.34 286.38,180.34 SV4.16
DAR09  (via drill 0.61)  (3 unrouted)
  Top 0.254: v34.29,77.47 v34.29,66.04 | v22.86,80.64 22.86,83.19 SV2.18 | IC4.11 109.22,146.05 109.22,147.32 120.65,147.32 121.92,146.05 121.92,127 122.56,126.36 122.56,114.3 123.19,113.67 123.19,106.05 122.56,105.41 122.56,83.19 v121.92,82.55 121.92,79.38 v121.28,78.74 | IC43.3 243.84,7.62 243.84,18.41 245.11,19.68 245.11,22.86 244.47,23.5 244.47,29.84 IC42.3 244.47,31.11 244.47,32.38 245.11,33.02 245.11,46.99 244.47,47.62 244.47,55.88 RF08A.5 | IC45.3 243.84,72.39 245.11,73.66 245.11,87.63 243.84,88.9 243.84,95.25 IC39.3 243.84,97.79 245.11,99.06 245.11,113.03 244.47,113.67 244.47,120.65 243.84,121.28 RF08B.5 | v205.74,177.16 205.74,177.8 203.84,179.71 IC51.5 | v281.94,177.16 283.21,178.44 v283.21,182.88
  Bottom 0.254: v34.29,66.04 37.47,66.04 RS08.5 | v22.86,80.64 31.11,80.64 v34.29,77.47 34.92,76.83 66.04,76.83 67.94,78.74 90.17,78.74 90.81,79.38 92.71,79.38 93.34,78.74 v121.28,78.74 | IC24.15 171.45,86.36 167.64,82.55 152.4,82.55 151.13,81.28 DAR8-11.6 148.59,81.28 147.32,82.55 v121.92,82.55 | 51.44,146.69 27.3,146.69 26.04,145.41 IC1.11 | 51.44,146.69 52.7,145.41 IC2.11 | 79.38,146.69 80.64,145.41 IC3.11 | 79.38,146.69 51.44,146.69 | 79.38,146.69 107.31,146.69 108.58,145.41 IC4.11 | v205.74,177.16 207.01,175.9 207.65,175.9 208.91,177.16 v281.94,177.16 | v283.21,182.88 286.38,182.88 SV4.18
DAR10  (via drill 0.61)  (3 unrouted)
  Top 0.254: v175.9,84.45 v175.9,92.71 175.26,93.34 175.26,134.62 173.99,135.89 173.99,138.43 169.54,142.88 156.21,142.88 156.21,144.15 155.57,144.78 147.96,144.78 v147.96,136.53 | v152.4,92.71 151.13,91.44 DAR8-11.2 | v20.32,74.93 20.32,83.19 SV2.20 20.32,84.45 19.05,85.72 19.05,99.69 v17.78,100.97 | v41.91,72.39 43.81,70.48 43.81,62.87 43.18,62.23 v43.18,60.96 | v24.13,134.62 24.13,130.81 21.59,128.27 6.35,128.27 v6.35,100.33 | IC43.28 248.92,22.86 248.92,27.3 247.65,28.57 247.65,31.75 248.92,33.02 248.92,44.45 IC42.28 248.92,46.99 248.92,52.7 247.65,53.98 247.65,57.78 248.28,58.42 RF08A.10 | IC45.28 248.92,87.63 248.28,88.27 248.28,94.61 247.65,95.25 247.65,106.05 248.92,107.31 248.92,110.49 IC39.28 248.92,113.03 247.65,114.3 247.65,122.56 248.92,123.83 RF08B.10 | v275.59,182.25 275.59,177.8 264.16,177.8 262.25,179.71 IC53.1
  Bottom 0.254: v175.9,84.45 173.35,81.92 IC24.13 | v175.9,92.71 v152.4,92.71 | v20.32,74.93 24.13,74.93 26.67,72.39 v41.91,72.39 | v43.18,60.96 41.27,60.96 RS08.10 | v147.96,136.53 146.05,134.62 119.38,134.62 114.94,130.18 34.92,130.18 30.48,134.62 v24.13,134.62 | v6.35,100.33 6.99,100.97 v17.78,100.97 | v275.59,182.25 281.94,182.25 282.57,181.61 290.19,181.61 290.83,182.25 290.83,186.69 288.93,186.69 287.65,185.42 SV4.20
DAR11  (via drill 0.61)  (3 unrouted)
  Top 0.254: v153.67,76.2 153.67,85.09 150.5,88.27 DAR8-11.3 | v17.78,65.41 17.78,83.19 SV2.22 | v144.78,88.9 144.78,105.41 145.41,106.05 145.41,108.58 143.51,110.49 143.51,115.57 140.97,118.11 140.97,120.65 140.34,121.28 138.43,121.28 138.43,100.33 137.79,99.69 137.79,99.06 138.43,98.42 v138.43,93.98 | v95.25,92.71 93.34,90.81 v93.34,83.19 | v39.37,80.64 38.1,79.38 38.1,73.03 36.83,71.75 36.83,65.41 38.1,64.14 RS08.7 | IC43.4 246.38,7.62 246.38,18.41 247.65,19.68 247.65,22.86 247.01,23.5 247.01,29.84 IC42.4 247.01,31.11 247.01,32.38 247.65,33.02 247.65,46.99 247.01,47.62 247.01,55.88 RF08A.7 | IC45.4 246.38,72.39 247.65,73.66 247.65,93.98 246.38,95.25 IC39.4 246.38,97.79 246.38,106.05 247.65,107.31 247.65,113.03 247.01,113.67 247.01,120.65 246.38,121.28 RF08B.7 | v269.24,184.15 266.7,181.61 IC53.3 | v281.94,185.42 283.21,186.69 v283.21,187.96
  Bottom 0.254: v153.67,76.2 154.94,74.93 170.18,74.93 171.45,76.2 IC24.11 | v17.78,65.41 18.41,64.77 32.38,64.77 33.66,63.5 37.47,63.5 RS08.7 | v144.78,88.9 148.59,88.9 DAR8-11.3 | v138.43,93.98 137.16,92.71 v95.25,92.71 | v93.34,83.19 92.08,81.92 52.07,81.92 50.8,80.64 v39.37,80.64 | v269.24,184.15 270.51,185.42 v281.94,185.42 | v283.21,187.96 286.38,187.96 SV4.22
DATA00\
  Bottom 0.254: IC34.12 29.21,20.32 27.94,19.05 15.88,19.05 12.7,22.23 C35L.2
DATA01\
  Bottom 0.254: IC34.14 29.21,25.4 28.57,26.04 24.77,26.04 24.13,26.67 14.61,26.67 13.34,25.4 C35L.4
DATA02\
  Bottom 0.254: IC34.16 29.21,30.48 25.4,30.48 24.13,29.21 14.61,29.21 13.34,27.94 C35L.6
DATA03\
  Bottom 0.254: IC34.18 29.21,35.56 28.57,34.92 24.77,34.92 24.13,34.29 18.41,34.29 15.88,31.75 14.61,31.75 13.34,30.48 C35L.8
DATA04\
  Bottom 0.254: IC26.3 21.59,68.58 20.32,67.31 10.16,67.31 4.45,61.59 4.45,33.66 12.7,33.66 C35L.10
DATA05\  (via drill 0.61)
